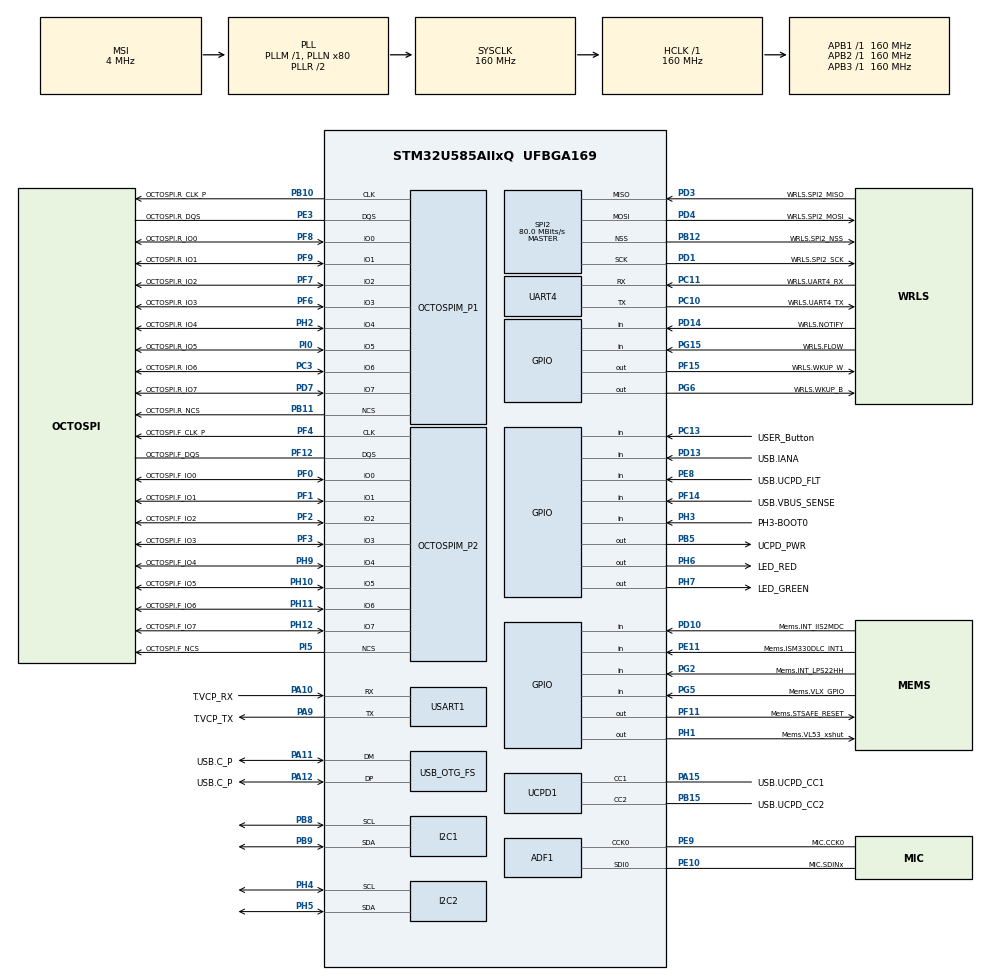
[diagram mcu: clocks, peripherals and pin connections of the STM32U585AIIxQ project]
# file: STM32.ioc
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CORTEX_M33_NS.userName=CORTEX_M33
I2C1.Timing=0x30909DEC
I2C2.Timing=0x30909DEC
Mcu.Family=STM32U5
Mcu.Name=STM32U585AIIxQ
Mcu.Package=UFBGA169
NVIC.PriorityGroup=NVIC_PRIORITYGROUP_4
OCTOSPI1.ChipSelectBoundary=10
OCTOSPI1.ClockPrescaler=2
OCTOSPI1.DelayBlockBypass=HAL_OSPI_DELAY_BLOCK_USED
OCTOSPI1.DelayHoldQuarterCycle=HAL_OSPI_DHQC_ENABLE
OCTOSPI1.DeviceSize=23
OCTOSPI1.MemoryType=HAL_OSPI_MEMTYPE_APMEMORY
OCTOSPI1.Refresh=100
OCTOSPI2.ChipSelectBoundary=0
OCTOSPI2.ChipSelectHighTime=2
OCTOSPI2.ClockPrescaler=4
OCTOSPI2.DelayBlockBypass=HAL_OSPI_DELAY_BLOCK_USED
OCTOSPI2.DelayHoldQuarterCycle=HAL_OSPI_DHQC_ENABLE
OCTOSPI2.DeviceSize=26
OCTOSPI2.FifoThreshold=4
OCTOSPI2.MemoryType=HAL_OSPI_MEMTYPE_MACRONIX
PA10.GPIO_Label=T.VCP_RX
PA10.Mode=Asynchronous
PA10.Signal=USART1_RX
PA11.GPIO_Label=USB.C_P
PA11.Mode=Device_Only
PA11.Signal=USB_OTG_FS_DM
PA12.GPIO_Label=USB.C_P
PA12.Mode=Device_Only
PA12.Signal=USB_OTG_FS_DP
PA13\ (JTMS/SWDIO).GPIO_Label=T.SWDIO
PA13\ (JTMS/SWDIO).Mode=Trace_Asynchronous_SW
PA13\ (JTMS/SWDIO).Signal=DEBUG_JTMS-SWDIO
PA14\ (JTCK/SWCLK).GPIO_Label=T.SWCLK
PA14\ (JTCK/SWCLK).Mode=Trace_Asynchronous_SW
PA14\ (JTCK/SWCLK).Signal=DEBUG_JTCK-SWCLK
PA15\ (JTDI).GPIO_Label=USB.UCPD_CC1
PA15\ (JTDI).Mode=Dual_Role_AllSignals
PA15\ (JTDI).Signal=UCPD1_CC1
PA9.GPIO_Label=T.VCP_TX
PA9.Mode=Asynchronous
PA9.Signal=USART1_TX
PB1.GPIO_Label=MIC.SDIN0
PB1.Signal=MDF1_SDI0
PB10.GPIO_Label=OCTOSPI.R_CLK_P
PB10.Mode=O1_P1_CLK
PB10.Signal=OCTOSPIM_P1_CLK
PB11.GPIO_Label=OCTOSPI.R_NCS
PB11.Mode=OCTOSPI1_Port1_NCS
PB11.Signal=OCTOSPIM_P1_NCS
PB12.GPIO_Label=WRLS.SPI2_NSS
PB12.Mode=NSS_Signal_Hard_Output
PB12.Signal=SPI2_NSS
PB15.GPIO_Label=USB.UCPD_CC2
PB15.Mode=Dual_Role_AllSignals
PB15.Signal=UCPD1_CC2
PB3\ (JTDO/TRACESWO).GPIO_Label=T.SWO
PB3\ (JTDO/TRACESWO).Mode=Trace_Asynchronous_SW
PB3\ (JTDO/TRACESWO).Signal=DEBUG_JTDO-SWO
PB5.GPIO_Label=UCPD_PWR
PB5.Signal=GPIO_Output
PB8.Mode=I2C
PB8.Signal=I2C1_SCL
PB9.Mode=I2C
PB9.Signal=I2C1_SDA
PC10.GPIO_Label=WRLS.UART4_TX
PC10.Mode=Asynchronous
PC10.Signal=UART4_TX
PC11.GPIO_Label=WRLS.UART4_RX
PC11.Mode=Asynchronous
PC11.Signal=UART4_RX
PC13.GPIO_Label=USER_Button
PC13.Signal=GPIO_Input
PC14-OSC32_IN\ (PC14).GPIO_Label=PC14-OSC32_IN
PC14-OSC32_IN\ (PC14).Mode=LSE-External-Oscillator
PC14-OSC32_IN\ (PC14).Signal=RCC_OSC32_IN
PC15-OSC32_OUT\ (PC15).GPIO_Label=PC15-OSC32_OUT
PC15-OSC32_OUT\ (PC15).Mode=LSE-External-Oscillator
PC15-OSC32_OUT\ (PC15).Signal=RCC_OSC32_OUT
PC3.GPIO_Label=OCTOSPI.R_IO6
PC3.Mode=OCTOSPI1_IOH_Port1H
PC3.Signal=OCTOSPIM_P1_IO6
PD1.GPIO_Label=WRLS.SPI2_SCK
PD1.Mode=Full_Duplex_Master
PD1.Signal=SPI2_SCK
PD10.GPIO_Label=Mems.INT_IIS2MDC
PD10.Signal=GPIO_Input
PD13.GPIO_Label=USB.IANA
PD13.Signal=GPIO_Input
PD14.GPIO_Label=WRLS.NOTIFY
PD14.Signal=GPIO_Input
PD3.GPIO_Label=WRLS.SPI2_MISO
PD3.Mode=Full_Duplex_Master
PD3.Signal=SPI2_MISO
PD4.GPIO_Label=WRLS.SPI2_MOSI
PD4.Mode=Full_Duplex_Master
PD4.Signal=SPI2_MOSI
PD7.GPIO_Label=OCTOSPI.R_IO7
PD7.Mode=OCTOSPI1_IOH_Port1H
PD7.Signal=OCTOSPIM_P1_IO7
PE10.GPIO_Label=MIC.SDINx
PE10.Mode=MOD_ADF_CCK
PE10.Signal=ADF1_SDI0
PE11.GPIO_Label=Mems.ISM330DLC_INT1
PE11.Signal=GPIO_Input
PE3.GPIO_Label=OCTOSPI.R_DQS
PE3.Mode=OCTOSPI1_Port1_DQS
PE3.Signal=OCTOSPIM_P1_DQS
PE8.GPIO_Label=USB.UCPD_FLT
PE8.Signal=GPIO_Input
PE9.GPIO_Label=MIC.CCK0
PE9.Mode=MOD_MDF_CCK0
PE9.Signal=ADF1_CCK0
PF0.GPIO_Label=OCTOSPI.F_IO0
PF0.Mode=OCTOSPI2_IOL_Port2L
PF0.Signal=OCTOSPIM_P2_IO0
PF1.GPIO_Label=OCTOSPI.F_IO1
PF1.Mode=OCTOSPI2_IOL_Port2L
PF1.Signal=OCTOSPIM_P2_IO1
PF10.GPIO_Label=MIC.CCK1
PF10.Signal=MDF1_CCK1
PF11.GPIO_Label=Mems.STSAFE_RESET
PF11.Signal=GPIO_Output
PF12.GPIO_Label=OCTOSPI.F_DQS
PF12.Mode=OCTOSPI2_Port2_DQS
PF12.Signal=OCTOSPIM_P2_DQS
PF14.GPIO_Label=USB.VBUS_SENSE
PF14.Signal=GPIO_Input
PF15.GPIO_Label=WRLS.WKUP_W
PF15.Signal=GPIO_Output
PF2.GPIO_Label=OCTOSPI.F_IO2
PF2.Mode=OCTOSPI2_IOL_Port2L
PF2.Signal=OCTOSPIM_P2_IO2
PF3.GPIO_Label=OCTOSPI.F_IO3
PF3.Mode=OCTOSPI2_IOL_Port2L
PF3.Signal=OCTOSPIM_P2_IO3
PF4.GPIO_Label=OCTOSPI.F_CLK_P
PF4.Mode=O2_P2_CLK
PF4.Signal=OCTOSPIM_P2_CLK
PF6.GPIO_Label=OCTOSPI.R_IO3
PF6.Mode=OCTOSPI1_IOL_Port1L
PF6.Signal=OCTOSPIM_P1_IO3
PF7.GPIO_Label=OCTOSPI.R_IO2
PF7.Mode=OCTOSPI1_IOL_Port1L
PF7.Signal=OCTOSPIM_P1_IO2
PF8.GPIO_Label=OCTOSPI.R_IO0
PF8.Mode=OCTOSPI1_IOL_Port1L
PF8.Signal=OCTOSPIM_P1_IO0
PF9.GPIO_Label=OCTOSPI.R_IO1
PF9.Mode=OCTOSPI1_IOL_Port1L
PF9.Signal=OCTOSPIM_P1_IO1
PG15.GPIO_Label=WRLS.FLOW
PG15.Signal=GPIO_Input
PG2.GPIO_Label=Mems.INT_LPS22HH
PG2.Signal=GPIO_Input
PG5.GPIO_Label=Mems.VLX_GPIO
PG5.Signal=GPIO_Input
PG6.GPIO_Label=WRLS.WKUP_B
PG6.Signal=GPIO_Output
PH1-OSC_OUT\ (PH1).GPIO_Label=Mems.VL53_xshut
PH1-OSC_OUT\ (PH1).Signal=GPIO_Output
PH10.GPIO_Label=OCTOSPI.F_IO5
PH10.Mode=OCTOSPI2_IOH_Port2H
PH10.Signal=OCTOSPIM_P2_IO5
PH11.GPIO_Label=OCTOSPI.F_IO6
PH11.Mode=OCTOSPI2_IOH_Port2H
PH11.Signal=OCTOSPIM_P2_IO6
PH12.GPIO_Label=OCTOSPI.F_IO7
PH12.Mode=OCTOSPI2_IOH_Port2H
PH12.Signal=OCTOSPIM_P2_IO7
PH2.GPIO_Label=OCTOSPI.R_IO4
PH2.Mode=OCTOSPI1_IOH_Port1H
PH2.Signal=OCTOSPIM_P1_IO4
PH3-BOOT0.GPIO_Label=PH3-BOOT0
PH3-BOOT0.Signal=GPIO_Input
PH4.Mode=I2C
PH4.Signal=I2C2_SCL
PH5.Mode=I2C
PH5.Signal=I2C2_SDA
PH6.GPIO_Label=LED_RED
PH6.Signal=GPIO_Output
PH7.GPIO_Label=LED_GREEN
PH7.Signal=GPIO_Output
PH9.GPIO_Label=OCTOSPI.F_IO4
PH9.Mode=OCTOSPI2_IOH_Port2H
PH9.Signal=OCTOSPIM_P2_IO4
PI0.GPIO_Label=OCTOSPI.R_IO5
PI0.Mode=OCTOSPI1_IOH_Port1H
PI0.Signal=OCTOSPIM_P1_IO5
PI5.GPIO_Label=OCTOSPI.F_NCS
PI5.Mode=OCTOSPI2_Port2_NCS
PI5.Signal=OCTOSPIM_P2_NCS
PWR.PowerMode=PWR_SMPS_SUPPLY
ProjectManager.HeapSize=0x200
ProjectManager.StackSize=0x400
ProjectManager.TargetToolchain=STM32CubeIDE
RCC.ADCFreq_Value=16000000
RCC.AHBFreq_Value=160000000
RCC.APB1Freq_Value=160000000
RCC.APB1TimFreq_Value=160000000
RCC.APB2Freq_Value=160000000
RCC.APB2TimFreq_Value=160000000
RCC.APB3Freq_Value=160000000
RCC.CortexFreq_Value=160000000
RCC.DACCLockSelectionVirtual=RCC_DAC1CLKSOURCE_LSI
RCC.EPOD_VALUE=4000000
RCC.HCLKFreq_Value=160000000
RCC.HSE_VALUE=16000000
RCC.HSI48_VALUE=48000000
RCC.HSI_VALUE=16000000
RCC.LSIDIV_VALUE=32000
RCC.MSI_VALUE=4000000
RCC.PLLN=80
RCC.SYSCLKFreq_VALUE=160000000
RCC.SYSCLKSource=RCC_SYSCLKSOURCE_PLLCLK
RCC.USBFreq_Value=48000000
RCC.VCOOutputFreq_Value=320000000
SPI2.CalculateBaudRate=80.0 MBits/s
SPI2.Direction=SPI_DIRECTION_2LINES
SPI2.Mode=SPI_MODE_MASTER
SPI2.VirtualNSS=VM_NSSHARD
SPI2.VirtualType=VM_MASTER
USART1.VirtualMode-Asynchronous=VM_ASYNC
USB_OTG_FS.VirtualMode=Device_Only
VP_ICACHE_VS_ICACHE.Mode=DirectMappedCache
VP_LPBAMQUEUE_VS_QUEUE.Mode=QUEUEMODE
VP_LPBAM_VS_SIG1.Mode=SmartRun
VP_LPBAM_VS_SIG4.Mode=LPDMA1
VP_MEMORYMAP_VS_MEMORYMAP.Mode=CurAppReg
VP_OCTOSPI1_VS_octo.Mode=octo_mode
VP_OCTOSPI2_VS_octo.Mode=octo_mode
VP_PWR_VS_DBSignals.Mode=DisableDeadBatterySignals
VP_PWR_VS_LPOM.Mode=PowerOptimisation
VP_PWR_VS_SECSignals.Mode=Security/Privilege
VP_THREADX_VS_RTOSJjThreadXJjCoreJjDefault.Mode=Core_Default
board=B-U585I-IOT02A

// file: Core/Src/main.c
/* USER CODE BEGIN Header */
/**
  ******************************************************************************
  * @file           : main.c
  * @brief          : Main program body using ThreadX (LED + Battery Monitor)
  ******************************************************************************
  */
/* USER CODE END Header */
#include "app_threadx.h"
#include "main.h"

/* USER CODE BEGIN Includes */
#include <string.h>
#include <stdio.h>
#include <stdint.h>
#include "pca9685.h"
#include "mcp2515.h"
/* USER CODE END Includes */

MDF_HandleTypeDef AdfHandle0;
MDF_FilterConfigTypeDef AdfFilterConfig0;

I2C_HandleTypeDef hi2c1;
I2C_HandleTypeDef hi2c2;

OSPI_HandleTypeDef hospi1;
OSPI_HandleTypeDef hospi2;

SPI_HandleTypeDef hspi2;

UART_HandleTypeDef huart4;
UART_HandleTypeDef huart1;

PCD_HandleTypeDef hpcd_USB_OTG_FS;

/* USER CODE BEGIN PV */
char uart_buf[64];
/* USER CODE END PV */

void SystemClock_Config(void);
static void SystemPower_Config(void);
static void MX_GPIO_Init(void);
static void MX_ADF1_Init(void);
static void MX_I2C1_Init(void);
static void MX_I2C2_Init(void);
static void MX_ICACHE_Init(void);
static void MX_OCTOSPI1_Init(void);
static void MX_OCTOSPI2_Init(void);
static void MX_SPI2_Init(void);
static void MX_UART4_Init(void);
static void MX_USART1_UART_Init(void);
static void MX_UCPD1_Init(void);
static void MX_USB_OTG_FS_PCD_Init(void);
/* USER CODE BEGIN PFP */
void Debug_Print(const char *msg);
void PCA9685_SetServoAngle(uint8_t channel, float angle);
/* USER CODE END PFP */

int main(void)
{

  /* MCU Configuration--------------------------------------------------------*/

  /* Reset of all peripherals, Initializes the Flash interface and the Systick. */
  HAL_Init();

  /* Configure the System Power */
  SystemPower_Config();

  /* Configure the system clock */
  SystemClock_Config();

  /* Initialize all configured peripherals */
  MX_GPIO_Init();
  MX_ADF1_Init();
  MX_I2C1_Init();
  MX_I2C2_Init();
  MX_ICACHE_Init();
  MX_OCTOSPI1_Init();
  MX_OCTOSPI2_Init();
  MX_SPI2_Init();
  MX_UART4_Init();
  MX_USART1_UART_Init();
  MX_UCPD1_Init();
  MX_USB_OTG_FS_PCD_Init();

  MX_ThreadX_Init();

  /* We should never get here as control is now taken by the scheduler */

  /* Infinite loop */
  while (1)
  {

  }
}

void SystemClock_Config(void)
{
  RCC_OscInitTypeDef RCC_OscInitStruct = {0};
  RCC_ClkInitTypeDef RCC_ClkInitStruct = {0};

  /** Configure the main internal regulator output voltage
  */
  if (HAL_PWREx_ControlVoltageScaling(PWR_REGULATOR_VOLTAGE_SCALE1) != HAL_OK)
  {
    Error_Handler();
  }

  /** Initializes the CPU, AHB and APB buses clocks
  */
  RCC_OscInitStruct.OscillatorType = RCC_OSCILLATORTYPE_HSI48|RCC_OSCILLATORTYPE_HSI
                              |RCC_OSCILLATORTYPE_MSI;
  RCC_OscInitStruct.HSIState = RCC_HSI_ON;
  RCC_OscInitStruct.HSI48State = RCC_HSI48_ON;
  RCC_OscInitStruct.HSICalibrationValue = RCC_HSICALIBRATION_DEFAULT;
  RCC_OscInitStruct.MSIState = RCC_MSI_ON;
  RCC_OscInitStruct.MSICalibrationValue = RCC_MSICALIBRATION_DEFAULT;
  RCC_OscInitStruct.MSIClockRange = RCC_MSIRANGE_4;
  RCC_OscInitStruct.PLL.PLLState = RCC_PLL_ON;
  RCC_OscInitStruct.PLL.PLLSource = RCC_PLLSOURCE_MSI;
  RCC_OscInitStruct.PLL.PLLMBOOST = RCC_PLLMBOOST_DIV1;
  RCC_OscInitStruct.PLL.PLLM = 1;
  RCC_OscInitStruct.PLL.PLLN = 80;
  RCC_OscInitStruct.PLL.PLLP = 2;
  RCC_OscInitStruct.PLL.PLLQ = 2;
  RCC_OscInitStruct.PLL.PLLR = 2;
  RCC_OscInitStruct.PLL.PLLRGE = RCC_PLLVCIRANGE_0;
  RCC_OscInitStruct.PLL.PLLFRACN = 0;
  if (HAL_RCC_OscConfig(&RCC_OscInitStruct) != HAL_OK)
  {
    Error_Handler();
  }

  /** Initializes the CPU, AHB and APB buses clocks
  */
  RCC_ClkInitStruct.ClockType = RCC_CLOCKTYPE_HCLK|RCC_CLOCKTYPE_SYSCLK
                              |RCC_CLOCKTYPE_PCLK1|RCC_CLOCKTYPE_PCLK2
                              |RCC_CLOCKTYPE_PCLK3;
  RCC_ClkInitStruct.SYSCLKSource = RCC_SYSCLKSOURCE_PLLCLK;
  RCC_ClkInitStruct.AHBCLKDivider = RCC_SYSCLK_DIV1;
  RCC_ClkInitStruct.APB1CLKDivider = RCC_HCLK_DIV1;
  RCC_ClkInitStruct.APB2CLKDivider = RCC_HCLK_DIV1;
  RCC_ClkInitStruct.APB3CLKDivider = RCC_HCLK_DIV1;

  if (HAL_RCC_ClockConfig(&RCC_ClkInitStruct, FLASH_LATENCY_4) != HAL_OK)
  {
    Error_Handler();
  }
}

/**
  * @brief Power Configuration
  * @retval None
  */
static void SystemPower_Config(void)
{
  HAL_PWREx_EnableVddIO2();

  /*
   * Switch to SMPS regulator instead of LDO
   */
  if (HAL_PWREx_ConfigSupply(PWR_SMPS_SUPPLY) != HAL_OK)
  {
    Error_Handler();
  }
}

static void MX_ADF1_Init(void)
{

  /**
    AdfHandle0 structure initialization and HAL_MDF_Init function call
  */
  AdfHandle0.Instance = ADF1_Filter0;
  AdfHandle0.Init.CommonParam.ProcClockDivider = 1;
  AdfHandle0.Init.CommonParam.OutputClock.Activation = DISABLE;
  AdfHandle0.Init.SerialInterface.Activation = ENABLE;
  AdfHandle0.Init.SerialInterface.Mode = MDF_SITF_LF_MASTER_SPI_MODE;
  AdfHandle0.Init.SerialInterface.ClockSource = MDF_SITF_CCK0_SOURCE;
  AdfHandle0.Init.SerialInterface.Threshold = 4;
  AdfHandle0.Init.FilterBistream = MDF_BITSTREAM0_FALLING;
  if (HAL_MDF_Init(&AdfHandle0) != HAL_OK)
  {
    Error_Handler();
  }

  /**
    AdfFilterConfig0 structure initialization

    WARNING : only structure is filled, no specific init function call for filter
  */
  AdfFilterConfig0.DataSource = MDF_DATA_SOURCE_BSMX;
  AdfFilterConfig0.Delay = 0;
  AdfFilterConfig0.CicMode = MDF_ONE_FILTER_SINC4;
  AdfFilterConfig0.DecimationRatio = 2;
  AdfFilterConfig0.Gain = 0;
  AdfFilterConfig0.ReshapeFilter.Activation = DISABLE;
  AdfFilterConfig0.HighPassFilter.Activation = DISABLE;
  AdfFilterConfig0.SoundActivity.Activation = DISABLE;
  AdfFilterConfig0.AcquisitionMode = MDF_MODE_ASYNC_CONT;
  AdfFilterConfig0.FifoThreshold = MDF_FIFO_THRESHOLD_NOT_EMPTY;
  AdfFilterConfig0.DiscardSamples = 0;

}

static void MX_I2C1_Init(void)
{

  hi2c1.Instance = I2C1;
  hi2c1.Init.Timing = 0x30909DEC;
  hi2c1.Init.OwnAddress1 = 0;
  hi2c1.Init.AddressingMode = I2C_ADDRESSINGMODE_7BIT;
  hi2c1.Init.DualAddressMode = I2C_DUALADDRESS_DISABLE;
  hi2c1.Init.OwnAddress2 = 0;
  hi2c1.Init.OwnAddress2Masks = I2C_OA2_NOMASK;
  hi2c1.Init.GeneralCallMode = I2C_GENERALCALL_DISABLE;
  hi2c1.Init.NoStretchMode = I2C_NOSTRETCH_DISABLE;
  if (HAL_I2C_Init(&hi2c1) != HAL_OK)
  {
    Error_Handler();
  }

  /** Configure Analogue filter
  */
  if (HAL_I2CEx_ConfigAnalogFilter(&hi2c1, I2C_ANALOGFILTER_ENABLE) != HAL_OK)
  {
    Error_Handler();
  }

  /** Configure Digital filter
  */
  if (HAL_I2CEx_ConfigDigitalFilter(&hi2c1, 0) != HAL_OK)
  {
    Error_Handler();
  }

}

static void MX_I2C2_Init(void)
{

  hi2c2.Instance = I2C2;
  hi2c2.Init.Timing = 0x30909DEC;
  hi2c2.Init.OwnAddress1 = 0;
  hi2c2.Init.AddressingMode = I2C_ADDRESSINGMODE_7BIT;
  hi2c2.Init.DualAddressMode = I2C_DUALADDRESS_DISABLE;
  hi2c2.Init.OwnAddress2 = 0;
  hi2c2.Init.OwnAddress2Masks = I2C_OA2_NOMASK;
  hi2c2.Init.GeneralCallMode = I2C_GENERALCALL_DISABLE;
  hi2c2.Init.NoStretchMode = I2C_NOSTRETCH_DISABLE;
  if (HAL_I2C_Init(&hi2c2) != HAL_OK)
  {
    Error_Handler();
  }

  /** Configure Analogue filter
  */
  if (HAL_I2CEx_ConfigAnalogFilter(&hi2c2, I2C_ANALOGFILTER_ENABLE) != HAL_OK)
  {
    Error_Handler();
  }

  /** Configure Digital filter
  */
  if (HAL_I2CEx_ConfigDigitalFilter(&hi2c2, 0) != HAL_OK)
  {
    Error_Handler();
  }

}

static void MX_ICACHE_Init(void)
{

  /** Enable instruction cache in 1-way (direct mapped cache)
  */
  if (HAL_ICACHE_ConfigAssociativityMode(ICACHE_1WAY) != HAL_OK)
  {
    Error_Handler();
  }
  if (HAL_ICACHE_Enable() != HAL_OK)
  {
    Error_Handler();
  }

}

static void MX_OCTOSPI1_Init(void)
{

  OSPIM_CfgTypeDef sOspiManagerCfg = {0};
  HAL_OSPI_DLYB_CfgTypeDef HAL_OSPI_DLYB_Cfg_Struct = {0};

  /* OCTOSPI1 parameter configuration*/
  hospi1.Instance = OCTOSPI1;
  hospi1.Init.FifoThreshold = 1;
  hospi1.Init.DualQuad = HAL_OSPI_DUALQUAD_DISABLE;
  hospi1.Init.MemoryType = HAL_OSPI_MEMTYPE_APMEMORY;
  hospi1.Init.DeviceSize = 23;
  hospi1.Init.ChipSelectHighTime = 1;
  hospi1.Init.FreeRunningClock = HAL_OSPI_FREERUNCLK_DISABLE;
  hospi1.Init.ClockMode = HAL_OSPI_CLOCK_MODE_0;
  hospi1.Init.WrapSize = HAL_OSPI_WRAP_NOT_SUPPORTED;
  hospi1.Init.ClockPrescaler = 2;
  hospi1.Init.SampleShifting = HAL_OSPI_SAMPLE_SHIFTING_NONE;
  hospi1.Init.DelayHoldQuarterCycle = HAL_OSPI_DHQC_ENABLE;
  hospi1.Init.ChipSelectBoundary = 10;
  hospi1.Init.DelayBlockBypass = HAL_OSPI_DELAY_BLOCK_USED;
  hospi1.Init.MaxTran = 0;
  hospi1.Init.Refresh = 100;
  if (HAL_OSPI_Init(&hospi1) != HAL_OK)
  {
    Error_Handler();
  }
  sOspiManagerCfg.ClkPort = 1;
  sOspiManagerCfg.DQSPort = 1;
  sOspiManagerCfg.NCSPort = 1;
  sOspiManagerCfg.IOLowPort = HAL_OSPIM_IOPORT_1_LOW;
  sOspiManagerCfg.IOHighPort = HAL_OSPIM_IOPORT_1_HIGH;
  if (HAL_OSPIM_Config(&hospi1, &sOspiManagerCfg, HAL_OSPI_TIMEOUT_DEFAULT_VALUE) != HAL_OK)
  {
    Error_Handler();
  }
  HAL_OSPI_DLYB_Cfg_Struct.Units = 0;
  HAL_OSPI_DLYB_Cfg_Struct.PhaseSel = 0;
  if (HAL_OSPI_DLYB_SetConfig(&hospi1, &HAL_OSPI_DLYB_Cfg_Struct) != HAL_OK)
  {
    Error_Handler();
  }

}

static void MX_OCTOSPI2_Init(void)
{

  OSPIM_CfgTypeDef sOspiManagerCfg = {0};
  HAL_OSPI_DLYB_CfgTypeDef HAL_OSPI_DLYB_Cfg_Struct = {0};

  /* OCTOSPI2 parameter configuration*/
  hospi2.Instance = OCTOSPI2;
  hospi2.Init.FifoThreshold = 4;
  hospi2.Init.DualQuad = HAL_OSPI_DUALQUAD_DISABLE;
  hospi2.Init.MemoryType = HAL_OSPI_MEMTYPE_MACRONIX;
  hospi2.Init.DeviceSize = 26;
  hospi2.Init.ChipSelectHighTime = 2;
  hospi2.Init.FreeRunningClock = HAL_OSPI_FREERUNCLK_DISABLE;
  hospi2.Init.ClockMode = HAL_OSPI_CLOCK_MODE_0;
  hospi2.Init.WrapSize = HAL_OSPI_WRAP_NOT_SUPPORTED;
  hospi2.Init.ClockPrescaler = 4;
  hospi2.Init.SampleShifting = HAL_OSPI_SAMPLE_SHIFTING_NONE;
  hospi2.Init.DelayHoldQuarterCycle = HAL_OSPI_DHQC_ENABLE;
  hospi2.Init.ChipSelectBoundary = 0;
  hospi2.Init.DelayBlockBypass = HAL_OSPI_DELAY_BLOCK_USED;
  hospi2.Init.MaxTran = 0;
  hospi2.Init.Refresh = 0;
  if (HAL_OSPI_Init(&hospi2) != HAL_OK)
  {
    Error_Handler();
  }
  sOspiManagerCfg.ClkPort = 2;
  sOspiManagerCfg.DQSPort = 2;
  sOspiManagerCfg.NCSPort = 2;
  sOspiManagerCfg.IOLowPort = HAL_OSPIM_IOPORT_2_LOW;
  sOspiManagerCfg.IOHighPort = HAL_OSPIM_IOPORT_2_HIGH;
  if (HAL_OSPIM_Config(&hospi2, &sOspiManagerCfg, HAL_OSPI_TIMEOUT_DEFAULT_VALUE) != HAL_OK)
  {
    Error_Handler();
  }
  HAL_OSPI_DLYB_Cfg_Struct.Units = 0;
  HAL_OSPI_DLYB_Cfg_Struct.PhaseSel = 0;
  if (HAL_OSPI_DLYB_SetConfig(&hospi2, &HAL_OSPI_DLYB_Cfg_Struct) != HAL_OK)
  {
    Error_Handler();
  }

}

static void MX_SPI2_Init(void)
{

  SPI_AutonomousModeConfTypeDef HAL_SPI_AutonomousMode_Cfg_Struct = {0};

  /* SPI2 parameter configuration*/
  hspi2.Instance = SPI2;
  hspi2.Init.Mode = SPI_MODE_MASTER;
  hspi2.Init.Direction = SPI_DIRECTION_2LINES;
  hspi2.Init.DataSize = SPI_DATASIZE_4BIT;
  hspi2.Init.CLKPolarity = SPI_POLARITY_LOW;
  hspi2.Init.CLKPhase = SPI_PHASE_1EDGE;
  hspi2.Init.NSS = SPI_NSS_HARD_OUTPUT;
  hspi2.Init.BaudRatePrescaler = SPI_BAUDRATEPRESCALER_2;
  hspi2.Init.FirstBit = SPI_FIRSTBIT_MSB;
  hspi2.Init.TIMode = SPI_TIMODE_DISABLE;
  hspi2.Init.CRCCalculation = SPI_CRCCALCULATION_DISABLE;
  hspi2.Init.CRCPolynomial = 0x7;
  hspi2.Init.NSSPMode = SPI_NSS_PULSE_ENABLE;
  hspi2.Init.NSSPolarity = SPI_NSS_POLARITY_LOW;
  hspi2.Init.FifoThreshold = SPI_FIFO_THRESHOLD_01DATA;
  hspi2.Init.MasterSSIdleness = SPI_MASTER_SS_IDLENESS_00CYCLE;
  hspi2.Init.MasterInterDataIdleness = SPI_MASTER_INTERDATA_IDLENESS_00CYCLE;
  hspi2.Init.MasterReceiverAutoSusp = SPI_MASTER_RX_AUTOSUSP_DISABLE;
  hspi2.Init.MasterKeepIOState = SPI_MASTER_KEEP_IO_STATE_DISABLE;
  hspi2.Init.IOSwap = SPI_IO_SWAP_DISABLE;
  hspi2.Init.ReadyMasterManagement = SPI_RDY_MASTER_MANAGEMENT_INTERNALLY;
  hspi2.Init.ReadyPolarity = SPI_RDY_POLARITY_HIGH;
  if (HAL_SPI_Init(&hspi2) != HAL_OK)
  {
    Error_Handler();
  }
  HAL_SPI_AutonomousMode_Cfg_Struct.TriggerState = SPI_AUTO_MODE_DISABLE;
  HAL_SPI_AutonomousMode_Cfg_Struct.TriggerSelection = SPI_GRP1_GPDMA_CH0_TCF_TRG;
  HAL_SPI_AutonomousMode_Cfg_Struct.TriggerPolarity = SPI_TRIG_POLARITY_RISING;
  if (HAL_SPIEx_SetConfigAutonomousMode(&hspi2, &HAL_SPI_AutonomousMode_Cfg_Struct) != HAL_OK)
  {
    Error_Handler();
  }

}

static void MX_UART4_Init(void)
{

  huart4.Instance = UART4;
  huart4.Init.BaudRate = 115200;
  huart4.Init.WordLength = UART_WORDLENGTH_8B;
  huart4.Init.StopBits = UART_STOPBITS_1;
  huart4.Init.Parity = UART_PARITY_NONE;
  huart4.Init.Mode = UART_MODE_TX_RX;
  huart4.Init.HwFlowCtl = UART_HWCONTROL_NONE;
  huart4.Init.OverSampling = UART_OVERSAMPLING_16;
  huart4.Init.OneBitSampling = UART_ONE_BIT_SAMPLE_DISABLE;
  huart4.Init.ClockPrescaler = UART_PRESCALER_DIV1;
  huart4.AdvancedInit.AdvFeatureInit = UART_ADVFEATURE_NO_INIT;
  if (HAL_UART_Init(&huart4) != HAL_OK)
  {
    Error_Handler();
  }
  if (HAL_UARTEx_SetTxFifoThreshold(&huart4, UART_TXFIFO_THRESHOLD_1_8) != HAL_OK)
  {
    Error_Handler();
  }
  if (HAL_UARTEx_SetRxFifoThreshold(&huart4, UART_RXFIFO_THRESHOLD_1_8) != HAL_OK)
  {
    Error_Handler();
  }
  if (HAL_UARTEx_DisableFifoMode(&huart4) != HAL_OK)
  {
    Error_Handler();
  }

}

static void MX_USART1_UART_Init(void)
{

  huart1.Instance = USART1;
  huart1.Init.BaudRate = 115200;
  huart1.Init.WordLength = UART_WORDLENGTH_8B;
  huart1.Init.StopBits = UART_STOPBITS_1;
  huart1.Init.Parity = UART_PARITY_NONE;
  huart1.Init.Mode = UART_MODE_TX_RX;
  huart1.Init.HwFlowCtl = UART_HWCONTROL_NONE;
  huart1.Init.OverSampling = UART_OVERSAMPLING_16;
  huart1.Init.OneBitSampling = UART_ONE_BIT_SAMPLE_DISABLE;
  huart1.Init.ClockPrescaler = UART_PRESCALER_DIV1;
  huart1.AdvancedInit.AdvFeatureInit = UART_ADVFEATURE_NO_INIT;
  if (HAL_UART_Init(&huart1) != HAL_OK)
  {
    Error_Handler();
  }
  if (HAL_UARTEx_SetTxFifoThreshold(&huart1, UART_TXFIFO_THRESHOLD_1_8) != HAL_OK)
  {
    Error_Handler();
  }
  if (HAL_UARTEx_SetRxFifoThreshold(&huart1, UART_RXFIFO_THRESHOLD_1_8) != HAL_OK)
  {
    Error_Handler();
  }
  if (HAL_UARTEx_DisableFifoMode(&huart1) != HAL_OK)
  {
    Error_Handler();
  }

}

static void MX_UCPD1_Init(void)
{

  LL_GPIO_InitTypeDef GPIO_InitStruct = {0};

  /* Peripheral clock enable */
  LL_APB1_GRP2_EnableClock(LL_APB1_GRP2_PERIPH_UCPD1);

  LL_AHB2_GRP1_EnableClock(LL_AHB2_GRP1_PERIPH_GPIOA);
  LL_AHB2_GRP1_EnableClock(LL_AHB2_GRP1_PERIPH_GPIOB);
  /**UCPD1 GPIO Configuration
  PA15 (JTDI)   ------> UCPD1_CC1
  PB15   ------> UCPD1_CC2
  */
  GPIO_InitStruct.Pin = LL_GPIO_PIN_15;
  GPIO_InitStruct.Mode = LL_GPIO_MODE_ANALOG;
  GPIO_InitStruct.Pull = LL_GPIO_PULL_NO;
  LL_GPIO_Init(GPIOA, &GPIO_InitStruct);

  GPIO_InitStruct.Pin = LL_GPIO_PIN_15;
  GPIO_InitStruct.Mode = LL_GPIO_MODE_ANALOG;
  GPIO_InitStruct.Pull = LL_GPIO_PULL_NO;
  LL_GPIO_Init(GPIOB, &GPIO_InitStruct);

}

static void MX_USB_OTG_FS_PCD_Init(void)
{

  hpcd_USB_OTG_FS.Instance = USB_OTG_FS;
  hpcd_USB_OTG_FS.Init.dev_endpoints = 6;
  hpcd_USB_OTG_FS.Init.speed = PCD_SPEED_FULL;
  hpcd_USB_OTG_FS.Init.phy_itface = PCD_PHY_EMBEDDED;
  hpcd_USB_OTG_FS.Init.Sof_enable = DISABLE;
  hpcd_USB_OTG_FS.Init.low_power_enable = DISABLE;
  hpcd_USB_OTG_FS.Init.lpm_enable = DISABLE;
  hpcd_USB_OTG_FS.Init.battery_charging_enable = DISABLE;
  hpcd_USB_OTG_FS.Init.use_dedicated_ep1 = DISABLE;
  hpcd_USB_OTG_FS.Init.vbus_sensing_enable = DISABLE;
  hpcd_USB_OTG_FS.Init.dma_enable = DISABLE;
  if (HAL_PCD_Init(&hpcd_USB_OTG_FS) != HAL_OK)
  {
    Error_Handler();
  }

}

static void MX_GPIO_Init(void)
{
  GPIO_InitTypeDef GPIO_InitStruct = {0};

  /* GPIO Ports Clock Enable */
  __HAL_RCC_GPIOG_CLK_ENABLE();
  __HAL_RCC_GPIOC_CLK_ENABLE();
  __HAL_RCC_GPIOA_CLK_ENABLE();
  __HAL_RCC_GPIOI_CLK_ENABLE();
  __HAL_RCC_GPIOH_CLK_ENABLE();
  __HAL_RCC_GPIOB_CLK_ENABLE();
  __HAL_RCC_GPIOD_CLK_ENABLE();
  __HAL_RCC_GPIOE_CLK_ENABLE();
  __HAL_RCC_GPIOF_CLK_ENABLE();

  /*Configure GPIO pin Output Level */
  HAL_GPIO_WritePin(UCPD_PWR_GPIO_Port, UCPD_PWR_Pin, GPIO_PIN_RESET);

  /*Configure GPIO pin Output Level */
  HAL_GPIO_WritePin(GPIOH, LED_RED_Pin|LED_GREEN_Pin|Mems_VL53_xshut_Pin, GPIO_PIN_RESET);

  /*Configure GPIO pin Output Level */
  HAL_GPIO_WritePin(WRLS_WKUP_B_GPIO_Port, WRLS_WKUP_B_Pin, GPIO_PIN_RESET);

  /*Configure GPIO pin Output Level */
  HAL_GPIO_WritePin(GPIOD, GPIO_PIN_15, GPIO_PIN_SET);

  /*Configure GPIO pin Output Level */
  HAL_GPIO_WritePin(GPIOD, GPIO_PIN_8, GPIO_PIN_RESET);

  /*Configure GPIO pin Output Level */
  HAL_GPIO_WritePin(GPIOF, Mems_STSAFE_RESET_Pin|GPIO_PIN_13|WRLS_WKUP_W_Pin, GPIO_PIN_RESET);

  /*Configure GPIO pins : WRLS_FLOW_Pin Mems_VLX_GPIO_Pin Mems_INT_LPS22HH_Pin */
  GPIO_InitStruct.Pin = WRLS_FLOW_Pin|Mems_VLX_GPIO_Pin|Mems_INT_LPS22HH_Pin;
  GPIO_InitStruct.Mode = GPIO_MODE_INPUT;
  GPIO_InitStruct.Pull = GPIO_NOPULL;
  HAL_GPIO_Init(GPIOG, &GPIO_InitStruct);

  /*Configure GPIO pin : PH3_BOOT0_Pin */
  GPIO_InitStruct.Pin = PH3_BOOT0_Pin;
  GPIO_InitStruct.Mode = GPIO_MODE_INPUT;
  GPIO_InitStruct.Pull = GPIO_NOPULL;
  HAL_GPIO_Init(PH3_BOOT0_GPIO_Port, &GPIO_InitStruct);

  /*Configure GPIO pin : UCPD_PWR_Pin */
  GPIO_InitStruct.Pin = UCPD_PWR_Pin;
  GPIO_InitStruct.Mode = GPIO_MODE_OUTPUT_PP;
  GPIO_InitStruct.Pull = GPIO_NOPULL;
  GPIO_InitStruct.Speed = GPIO_SPEED_FREQ_LOW;
  HAL_GPIO_Init(UCPD_PWR_GPIO_Port, &GPIO_InitStruct);

  /*Configure GPIO pin : USER_Button_Pin */
  GPIO_InitStruct.Pin = USER_Button_Pin;
  GPIO_InitStruct.Mode = GPIO_MODE_INPUT;
  GPIO_InitStruct.Pull = GPIO_NOPULL;
  HAL_GPIO_Init(USER_Button_GPIO_Port, &GPIO_InitStruct);

  /*Configure GPIO pins : LED_RED_Pin LED_GREEN_Pin Mems_VL53_xshut_Pin */
  GPIO_InitStruct.Pin = LED_RED_Pin|LED_GREEN_Pin|Mems_VL53_xshut_Pin;
  GPIO_InitStruct.Mode = GPIO_MODE_OUTPUT_PP;
  GPIO_InitStruct.Pull = GPIO_NOPULL;
  GPIO_InitStruct.Speed = GPIO_SPEED_FREQ_LOW;
  HAL_GPIO_Init(GPIOH, &GPIO_InitStruct);

  /*Configure GPIO pin : MIC_CCK1_Pin */
  GPIO_InitStruct.Pin = MIC_CCK1_Pin;
  GPIO_InitStruct.Mode = GPIO_MODE_AF_PP;
  GPIO_InitStruct.Pull = GPIO_NOPULL;
  GPIO_InitStruct.Speed = GPIO_SPEED_FREQ_LOW;
  GPIO_InitStruct.Alternate = GPIO_AF6_MDF1;
  HAL_GPIO_Init(MIC_CCK1_GPIO_Port, &GPIO_InitStruct);

  /*Configure GPIO pin : WRLS_WKUP_B_Pin */
  GPIO_InitStruct.Pin = WRLS_WKUP_B_Pin;
  GPIO_InitStruct.Mode = GPIO_MODE_OUTPUT_PP;
  GPIO_InitStruct.Pull = GPIO_NOPULL;
  GPIO_InitStruct.Speed = GPIO_SPEED_FREQ_LOW;
  HAL_GPIO_Init(WRLS_WKUP_B_GPIO_Port, &GPIO_InitStruct);

  /*Configure GPIO pins : WRLS_NOTIFY_Pin Mems_INT_IIS2MDC_Pin USB_IANA_Pin */
  GPIO_InitStruct.Pin = WRLS_NOTIFY_Pin|Mems_INT_IIS2MDC_Pin|USB_IANA_Pin;
  GPIO_InitStruct.Mode = GPIO_MODE_INPUT;
  GPIO_InitStruct.Pull = GPIO_NOPULL;
  HAL_GPIO_Init(GPIOD, &GPIO_InitStruct);

  /*Configure GPIO pins : PD15 PD8 */
  GPIO_InitStruct.Pin = GPIO_PIN_15|GPIO_PIN_8;
  GPIO_InitStruct.Mode = GPIO_MODE_OUTPUT_PP;
  GPIO_InitStruct.Pull = GPIO_NOPULL;
  GPIO_InitStruct.Speed = GPIO_SPEED_FREQ_HIGH;
  HAL_GPIO_Init(GPIOD, &GPIO_InitStruct);

  /*Configure GPIO pins : USB_UCPD_FLT_Pin Mems_ISM330DLC_INT1_Pin */
  GPIO_InitStruct.Pin = USB_UCPD_FLT_Pin|Mems_ISM330DLC_INT1_Pin;
  GPIO_InitStruct.Mode = GPIO_MODE_INPUT;
  GPIO_InitStruct.Pull = GPIO_NOPULL;
  HAL_GPIO_Init(GPIOE, &GPIO_InitStruct);

  /*Configure GPIO pin : USB_VBUS_SENSE_Pin */
  GPIO_InitStruct.Pin = USB_VBUS_SENSE_Pin;
  GPIO_InitStruct.Mode = GPIO_MODE_INPUT;
  GPIO_InitStruct.Pull = GPIO_NOPULL;
  HAL_GPIO_Init(USB_VBUS_SENSE_GPIO_Port, &GPIO_InitStruct);

  /*Configure GPIO pin : PE7 */
  GPIO_InitStruct.Pin = GPIO_PIN_7;
  GPIO_InitStruct.Mode = GPIO_MODE_IT_FALLING;
  GPIO_InitStruct.Pull = GPIO_PULLUP;
  HAL_GPIO_Init(GPIOE, &GPIO_InitStruct);

  /*Configure GPIO pin : PD9 */
  GPIO_InitStruct.Pin = GPIO_PIN_9;
  GPIO_InitStruct.Mode = GPIO_MODE_INPUT;
  GPIO_InitStruct.Pull = GPIO_PULLUP;
  HAL_GPIO_Init(GPIOD, &GPIO_InitStruct);

  /*Configure GPIO pins : Mems_STSAFE_RESET_Pin WRLS_WKUP_W_Pin */
  GPIO_InitStruct.Pin = Mems_STSAFE_RESET_Pin|WRLS_WKUP_W_Pin;
  GPIO_InitStruct.Mode = GPIO_MODE_OUTPUT_PP;
  GPIO_InitStruct.Pull = GPIO_NOPULL;
  GPIO_InitStruct.Speed = GPIO_SPEED_FREQ_LOW;
  HAL_GPIO_Init(GPIOF, &GPIO_InitStruct);

  /*Configure GPIO pin : PF13 */
  GPIO_InitStruct.Pin = GPIO_PIN_13;
  GPIO_InitStruct.Mode = GPIO_MODE_OUTPUT_PP;
  GPIO_InitStruct.Pull = GPIO_NOPULL;
  GPIO_InitStruct.Speed = GPIO_SPEED_FREQ_HIGH;
  HAL_GPIO_Init(GPIOF, &GPIO_InitStruct);

  /*Configure GPIO pin : MIC_SDIN0_Pin */
  GPIO_InitStruct.Pin = MIC_SDIN0_Pin;
  GPIO_InitStruct.Mode = GPIO_MODE_AF_PP;
  GPIO_InitStruct.Pull = GPIO_NOPULL;
  GPIO_InitStruct.Speed = GPIO_SPEED_FREQ_LOW;
  GPIO_InitStruct.Alternate = GPIO_AF6_MDF1;
  HAL_GPIO_Init(MIC_SDIN0_GPIO_Port, &GPIO_InitStruct);

  /* EXTI interrupt init*/
  HAL_NVIC_SetPriority(EXTI7_IRQn, 0, 0);
  HAL_NVIC_EnableIRQ(EXTI7_IRQn);

}

/* USER CODE BEGIN 4 */
void Battery_Thread_Entry(ULONG thread_input) {
    (void) thread_input;
    HAL_StatusTypeDef ret;

    // INA219 constants
    const uint8_t INA219_ADDR = 0x41 << 1;  // INA219 at 0x41
    const uint8_t INA219_REG_CONFIG = 0x00;
    const uint8_t INA219_REG_SHUNT_VOLTAGE = 0x01;
    const uint8_t INA219_REG_BUS_VOLTAGE = 0x02;
    const uint8_t INA219_REG_CURRENT = 0x04;

    Debug_Print("\r\n=== BATTERY MONITOR THREAD STARTED ===\r\n");
    Debug_Print("[BATTERY_THREAD] Running on ThreadX RTOS (Single Thread)\r\n");
    Debug_Print("[BATTERY_THREAD] This thread handles both LED blinking and battery monitoring\r\n");
    Debug_Print("[BATTERY_THREAD] Green LED will toggle every 2 seconds\r\n");

    // Initialize MCP2515 CAN controller
    Debug_Print("\r\n[CAN] Initializing MCP2515...\r\n");

    // Run connection test first
    MCP2515_TestConnection();

    if (MCP2515_Init(CAN_SPEED_500KBPS) == HAL_OK) {
        Debug_Print("[CAN] MCP2515 initialized successfully (500 kbps) - NORMAL MODE\r\n");
        MCP2515_PrintDetailedStatus();  // Print detailed initial status
    } else {
        Debug_Print("[CAN] MCP2515 initialization FAILED!\r\n");
        MCP2515_PrintDetailedStatus();  // Print detailed status to see what went wrong
    }

    // Reset I2C bus to clear any stuck state
    Debug_Print("[BATTERY_THREAD] Resetting I2C bus...\r\n");
    HAL_I2C_DeInit(&hi2c1);
    tx_thread_sleep(10);  // 100ms delay
    MX_I2C1_Init();
    tx_thread_sleep(10);  // 100ms delay
    Debug_Print("[BATTERY_THREAD] I2C bus reset complete\r\n");

    // Wait for system to stabilize
    Debug_Print("[BATTERY_THREAD] Waiting 1 second...\r\n");
    tx_thread_sleep(100);

    // Scan I2C bus for devices
    Debug_Print("\r\n[BATTERY_THREAD] Scanning I2C bus...\r\n");
    uint8_t found_count = 0;
    for (uint8_t addr = 0x01; addr < 0x7F; addr++) {
        if (HAL_I2C_IsDeviceReady(&hi2c1, addr << 1, 1, 100) == HAL_OK) {
            snprintf(uart_buf, sizeof(uart_buf), "  Device found at 0x%02X\r\n", addr);
            Debug_Print(uart_buf);
            found_count++;
        }
    }
    snprintf(uart_buf, sizeof(uart_buf), "[BATTERY_THREAD] Scan complete: %d devices found\r\n", found_count);
    Debug_Print(uart_buf);

    // Check if INA219 is present

    Debug_Print("\r\n[BATTERY_THREAD] Checking INA219 at 0x41\r\n");
    if (HAL_I2C_IsDeviceReady(&hi2c1, INA219_ADDR, 2, 200) == HAL_OK) {
        Debug_Print("[BATTERY_THREAD] INA219 found!\r\n");

        // Configure INA219: 16V range, 320mV shunt range, continuous mode
        uint8_t config_data[3] = {INA219_REG_CONFIG, 0x39, 0x9F};
        ret = HAL_I2C_Master_Transmit(&hi2c1, INA219_ADDR, config_data, 3, 200);
        if (ret == HAL_OK) {
            Debug_Print("[BATTERY_THREAD] INA219 configured!\r\n");
        } else {
            snprintf(uart_buf, sizeof(uart_buf), "[BATTERY_THREAD] INA219 config failed (status: %d)!\r\n", ret);
            Debug_Print(uart_buf);
        }
    } else {
        Debug_Print("[BATTERY_THREAD] INA219 not found!\r\n");
    }

    // Helper macro for concise init/test
  #define INIT_AND_TEST_PCA9685(addr, label) \
    do { \
      snprintf(uart_buf, sizeof(uart_buf), "[PCA9685] Init %s (0x%02X)\r\n", label, addr); Debug_Print(uart_buf); \
      uint8_t cmd1[2] = {0x00, 0x00}; HAL_I2C_Master_Transmit(&hi2c1, addr, cmd1, 2, 500); tx_thread_sleep(1); \
      uint8_t cmd2[2] = {0x01, 0x04}; HAL_I2C_Master_Transmit(&hi2c1, addr, cmd2, 2, 500); tx_thread_sleep(1); \
      uint8_t cmd3[2] = {0x00, 0x10}; HAL_I2C_Master_Transmit(&hi2c1, addr, cmd3, 2, 500); tx_thread_sleep(1); \
      uint8_t cmd4[2] = {0xFE, 121}; HAL_I2C_Master_Transmit(&hi2c1, addr, cmd4, 2, 500); tx_thread_sleep(1); \
      uint8_t cmd5[2] = {0x00, 0x80}; HAL_I2C_Master_Transmit(&hi2c1, addr, cmd5, 2, 500); tx_thread_sleep(1); \
      uint8_t mode1_reg = 0x00, mode1_val = 0; \
      HAL_I2C_Master_Transmit(&hi2c1, addr, &mode1_reg, 1, 500); \
      HAL_I2C_Master_Receive(&hi2c1, addr, &mode1_val, 1, 500); \
      snprintf(uart_buf, sizeof(uart_buf), "[PCA9685] MODE1: 0x%02X\r\n", mode1_val); Debug_Print(uart_buf); \
      ret = PCA9685_SetPWM(&hi2c1, addr, 0, 0, 307); \
      if (ret == HAL_OK) { \
        uint8_t on_l, on_h, off_l, off_h, reg; \
        reg = 0x06; HAL_I2C_Master_Transmit(&hi2c1, addr, &reg, 1, 500); HAL_I2C_Master_Receive(&hi2c1, addr, &on_l, 1, 500); \
        reg = 0x07; HAL_I2C_Master_Transmit(&hi2c1, addr, &reg, 1, 500); HAL_I2C_Master_Receive(&hi2c1, addr, &on_h, 1, 500); \
        reg = 0x08; HAL_I2C_Master_Transmit(&hi2c1, addr, &reg, 1, 500); HAL_I2C_Master_Receive(&hi2c1, addr, &off_l, 1, 500); \
        reg = 0x09; HAL_I2C_Master_Transmit(&hi2c1, addr, &reg, 1, 500); HAL_I2C_Master_Receive(&hi2c1, addr, &off_h, 1, 500); \
        uint16_t off_value = (off_h << 8) | off_l; \
        snprintf(uart_buf, sizeof(uart_buf), "[PCA9685] %s PWM: ON=%d OFF=%d (readback: %d)\r\n", label, 0, 307, off_value); Debug_Print(uart_buf); \
      } else { Debug_Print("[PCA9685] PWM write failed\r\n"); } \
    } while(0)

    INIT_AND_TEST_PCA9685(PCA9685_ADDR_THROTTLE, "Throttle");
    INIT_AND_TEST_PCA9685(PCA9685_ADDR_STEERING, "Steering");

    Debug_Print("[BATTERY_THREAD] PCA9685 test complete. Starting sweep test...\r\n\r\n");

    // --- STEERING SERVO SWEEP TEST ---
    for (float angle = -30.0f; angle <= 30.0f; angle += 5.0f) {
        PCA9685_SetServoAngle(0, angle); // Channel 0 for steering
        tx_thread_sleep(10); // 100ms per step
    }
    for (float angle = 30.0f; angle >= -30.0f; angle -= 5.0f) {
        PCA9685_SetServoAngle(0, angle);
        tx_thread_sleep(10);
    }
    Debug_Print("[SWEEP] Steering sweep complete\r\n");

    // Wait 1 second before throttle test
    tx_thread_sleep(100); // 1 second

    // --- THROTTLE MOTOR H-BRIDGE TEST (PCA9685 @ 0x60) ---
      // This test runs both motors forward at 50% duty for 2 seconds, then stops all motors.
      // Channels: 0 = M1 speed, 1 = M1 DIR1, 2 = M1 DIR2, 3 = M2 speed, 4 = M2 speed, 5 = M2 DIR2, 6 = M2 DIR1, 7 = M2 speed

      // Set both motors forward, 50% duty
      uint16_t speed_pwm = 2048; // 50% of 4095
      uint16_t dir_high = 4095;
      uint16_t dir_low = 0;

      // Motor 1 (channels 0,1,2,3)
      PCA9685_SetPWM(&hi2c1, PCA9685_ADDR_THROTTLE, 0, 0, speed_pwm); // M1 speed
      PCA9685_SetPWM(&hi2c1, PCA9685_ADDR_THROTTLE, 1, 0, dir_high);  // M1 DIR1 (forward)
      PCA9685_SetPWM(&hi2c1, PCA9685_ADDR_THROTTLE, 2, 0, dir_low);   // M1 DIR2 (reverse)
      PCA9685_SetPWM(&hi2c1, PCA9685_ADDR_THROTTLE, 3, 0, 0);         // M2 speed (off)

      // Motor 2 (channels 4,5,6,7)
      PCA9685_SetPWM(&hi2c1, PCA9685_ADDR_THROTTLE, 4, 0, speed_pwm); // M2 speed
      PCA9685_SetPWM(&hi2c1, PCA9685_ADDR_THROTTLE, 5, 0, dir_low);   // M2 DIR2 (reverse)
      PCA9685_SetPWM(&hi2c1, PCA9685_ADDR_THROTTLE, 6, 0, dir_high);  // M2 DIR1 (forward)
      PCA9685_SetPWM(&hi2c1, PCA9685_ADDR_THROTTLE, 7, 0, speed_pwm); // M2 speed

      Debug_Print("[THROTTLE TEST] Both motors forward 50%\r\n");
      tx_thread_sleep(200); // 2 seconds

      // Stop all motors (set all speed and direction channels to 0)
    for (uint8_t ch = 0; ch < 8; ++ch) {
      PCA9685_SetPWM(&hi2c1, PCA9685_ADDR_THROTTLE, ch, 0, 0);
    }
    Debug_Print("[THROTTLE TEST] Motors stopped\r\n\r\n");

    Debug_Print("[BATTERY_THREAD] Starting monitoring loop\r\n\r\n");

    uint32_t count = 0;
    uint8_t led_state = 0;
    uint8_t error_count = 0;

    while(1) {
        // Toggle green LED (runs independently from other threads)
        led_state = !led_state;
        HAL_GPIO_WritePin(LED_GREEN_GPIO_Port, LED_GREEN_Pin, led_state ? GPIO_PIN_SET : GPIO_PIN_RESET);

        // Read INA219 voltage and current with error recovery
        uint8_t reg_addr;
        uint8_t data[2];

        // Read bus voltage with retry
        reg_addr = INA219_REG_BUS_VOLTAGE;
        ret = HAL_I2C_Master_Transmit(&hi2c1, INA219_ADDR, &reg_addr, 1, 200);

        if (ret != HAL_OK) {
            // I2C error - try to recover
            error_count++;
            if (error_count > 3) {
                // Reset I2C peripheral
                __HAL_I2C_DISABLE(&hi2c1);
                tx_thread_sleep(5);  // 50ms delay
                __HAL_I2C_ENABLE(&hi2c1);
                error_count = 0;
                Debug_Print("[BATTERY_THREAD] I2C bus reset\r\n");
            }
            snprintf(uart_buf, sizeof(uart_buf), "[BATTERY_THREAD][%lu] I2C TX error: %d\r\n", count, ret);
            Debug_Print(uart_buf);
        } else {
            // Small delay before receive
            tx_thread_sleep(1);  // 10ms

            ret = HAL_I2C_Master_Receive(&hi2c1, INA219_ADDR, data, 2, 200);
            if (ret == HAL_OK) {
                error_count = 0;  // Reset error counter on success

                int16_t bus_voltage_raw = (data[0] << 8) | data[1];

                // Debug: show raw data
                if (count < 3) {  // Only for first 3 readings
                    snprintf(uart_buf, sizeof(uart_buf), "[DEBUG] Raw bytes: 0x%02X 0x%02X, raw_value: %d\r\n",
                            data[0], data[1], bus_voltage_raw);
                    Debug_Print(uart_buf);
                }

                bus_voltage_raw >>= 3;  // Remove lower 3 bits
                float voltage = bus_voltage_raw * 0.004f;  // 4mV per bit

                // Calculate battery percentage (9.5V = 0%, 12.6V = 100%)
                float percentage = ((voltage - 9.5f) / (12.6f - 9.5f)) * 100.0f;
                // Clamp percentage between 0% and 100%
                if (percentage > 100.0f) percentage = 100.0f;
                if (percentage < 0.0f) percentage = 0.0f;

                // Read current with delay
                tx_thread_sleep(1);  // 10ms
                reg_addr = INA219_REG_CURRENT;
                ret = HAL_I2C_Master_Transmit(&hi2c1, INA219_ADDR, &reg_addr, 1, 200);
                if (ret == HAL_OK) {
                    tx_thread_sleep(1);  // 10ms
                    ret = HAL_I2C_Master_Receive(&hi2c1, INA219_ADDR, data, 2, 200);
                    if (ret == HAL_OK) {
                        int16_t current_raw = (data[0] << 8) | data[1];
                        float current = current_raw * 0.001f;  // 1mA per bit (depends on calibration)

                        // Convert floats to integers for printf (floating point printf not enabled)
                        int voltage_int = (int)voltage;
                        int voltage_frac = (int)((voltage - voltage_int) * 100);
                        int percentage_int = (int)percentage;
                        int current_int = (int)current;

                        // Send battery percentage over CAN
                        HAL_StatusTypeDef can_status = MCP2515_SendBattery((uint8_t)percentage_int);
                        const char* can_status_str = (can_status == HAL_OK) ? "OK" :
                                                      (can_status == HAL_BUSY) ? "BUSY" :
                                                      (can_status == HAL_TIMEOUT) ? "TIMEOUT" : "ERROR";

                        snprintf(uart_buf, sizeof(uart_buf), "[BATTERY] %d.%02dV (%d%%), %dmA | CAN: %s \xF0\x9F\xA4\x91\r\n",
                                voltage_int, voltage_frac, percentage_int, current_int, can_status_str);
                        Debug_Print(uart_buf);

                        // Check for received CAN messages
                        MCP2515_CheckForMessages();

                        // Print detailed MCP2515 status every 10 iterations (20 seconds)
                        if (count % 10 == 0) {
                            MCP2515_PrintDetailedStatus();
                        }
                    } else {
                        error_count++;
                        snprintf(uart_buf, sizeof(uart_buf), "[BATTERY_THREAD][%lu] Current RX error: %d\r\n", count, ret);
                        Debug_Print(uart_buf);
                    }
                } else {
                    error_count++;
                    snprintf(uart_buf, sizeof(uart_buf), "[BATTERY_THREAD][%lu] Current TX error: %d\r\n", count, ret);
                    Debug_Print(uart_buf);
                }
            } else {
                error_count++;
                snprintf(uart_buf, sizeof(uart_buf), "[BATTERY_THREAD][%lu] Voltage RX error: %d\r\n", count, ret);
                Debug_Print(uart_buf);
            }
        }

        count++;
        tx_thread_sleep(200);  // 2 seconds (context switches to other threads)
    }
} // Properly close Battery_Thread_Entry

void Debug_Print(const char *msg) {
    HAL_UART_Transmit(&huart1, (uint8_t *)msg, strlen(msg), HAL_MAX_DELAY);
}

void PCA9685_SetServoAngle(uint8_t channel, float angle) {
    // Clamp angle to safe range
    if (angle < -30.0f) angle = -30.0f;
    if (angle > 30.0f) angle = 30.0f;

    // Convert angle to pulse width (1ms to 2ms)
    float pulse_center = 307.0f;
    float counts_per_degree = 2.27f;

    uint16_t pulse_width = (uint16_t)(pulse_center + (angle * counts_per_degree));

    // Set PWM: ON at 0, OFF at calculated pulse width
    PCA9685_SetPWM(&hi2c1, PCA9685_ADDR_STEERING, channel, 0, pulse_width);
}
/* USER CODE END 4 */

void HAL_TIM_PeriodElapsedCallback(TIM_HandleTypeDef *htim)
{
  if (htim->Instance == TIM6)
  {
    HAL_IncTick();
  }
}

void Error_Handler(void)
{
  /* USER CODE BEGIN Error_Handler_Debug */
  /* User can add his own implementation to report the HAL error return state */
  __disable_irq();
  // Blink red LED very fast to indicate error
  while (1)
  {
    HAL_GPIO_TogglePin(GPIOH, LED_RED_Pin);
    for(volatile uint32_t i = 0; i < 100000; i++);
  }
  /* USER CODE END Error_Handler_Debug */
}
